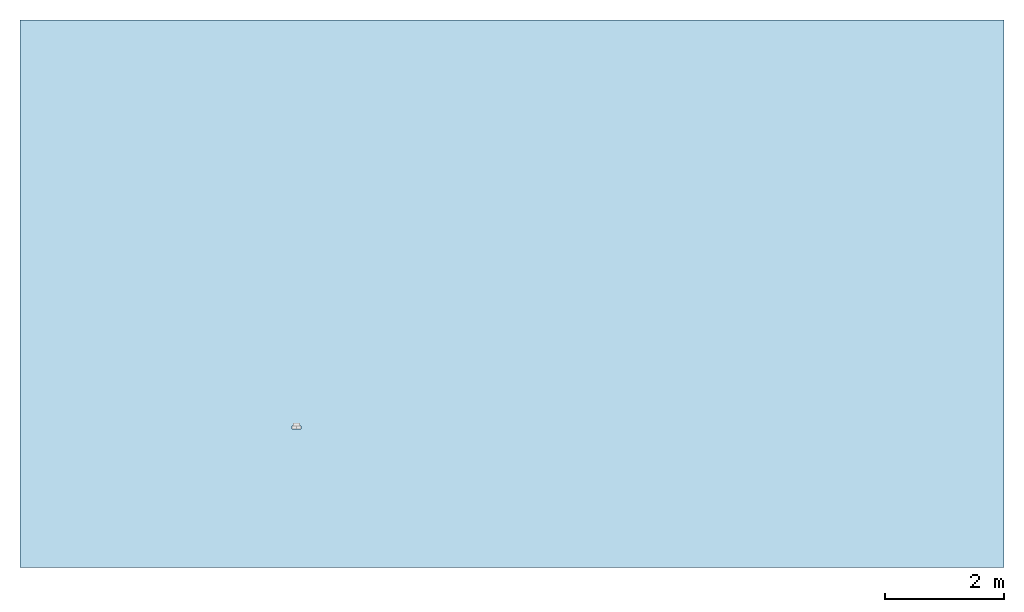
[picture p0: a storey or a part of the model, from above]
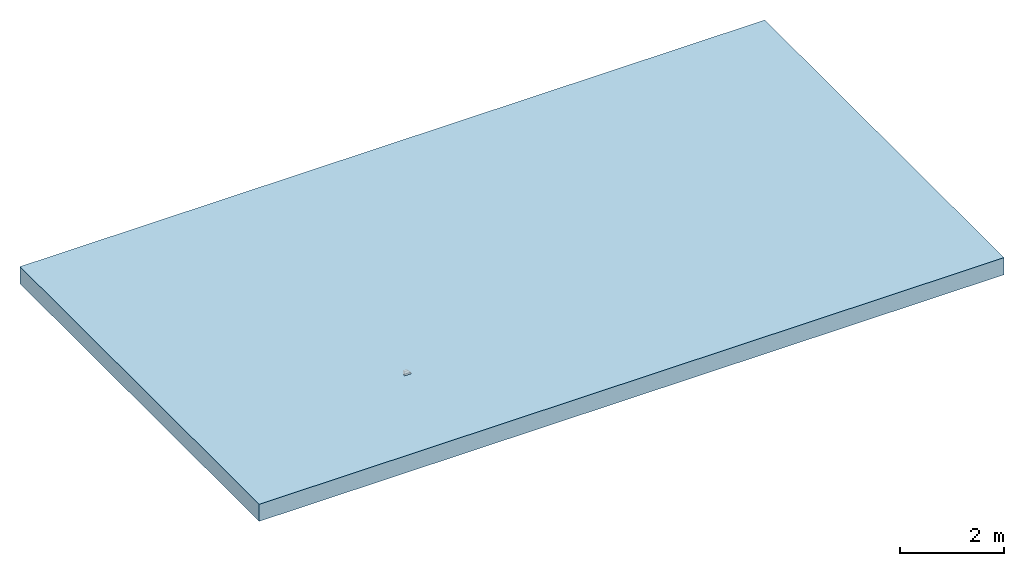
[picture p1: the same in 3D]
Properties of the parts of a building model (IFC2X3)

# File
Description: ViewDefinition [CoordinationView]
File name: 4247 - LH inlet-outlet end cap.ifc
Time: 2013-09-02T12:24:39
Written by: Autodesk Revit 2013
Made in: 20120221_2030(x64)

# IfcProject, Project Number
LongName: Project Name; Phase: Project Status

# IfcSite, Default
RefLatitude: 42, 21, 30, 344238; RefLongitude: -71, -3, -35, -194702; RefElevation: 0 mm

# IfcBuilding
Pset_BuildingCommon - NumberOfStoreys: 1
Other - Project Issue Date: Issue Date; Project Number: Project Number; Project Address: ## Street City, State Zip; Project Name: Project Name; Client Name: Owner; Project Status: Project Status

# IfcBuildingStorey, Level 1
LongName: Level 1; Elevation: 0 mm
Constraints - Elevation Base: 0; Elevation: 0 mm
Graphics - Line Weight: 1; Symbol: M_Level Head - Circle: M_Level Head - Circle; Symbol at End 2 Default: yes; Color: 0; Line Pattern: Center; Symbol at End 1 Default: no
Dimensions - Computation Height: 0 mm
Identity Data - Structural: no; Name: Level 1; Building Story: yes

# IfcBuildingElementProxy: 4247 - LH inlet/outlet end cap, Civil-Drainage-Channel-ACO-KerbDrain-SP380:4247 - LH inlet/outlet end cap:4247 - LH inlet/outlet end cap:308659
In: Level 1
Material: Orange, ACO Polymer Concrete.
Other - Revision: 1; CreatedBy: www.aco.co.uk
Constraints - Level: Level: Level 1; Moves With Nearby Elements: no
Phasing - Phase Created: New Construction
Dimensions - Volume: 2398380 mm3; Void Depth: -280 mm; Void Length: 50 mm; Void Width: 150 mm; AccessDepth: 2000 mm; Access hole: 2 mm; Endcap void: 329.99 mm
Pset_BuildingElementProxyCommon - Reference: 4247 - LH inlet/outlet end cap
Green Building Properties - End Cap Recycled Material Content: 20% minimum; End Cap Recyclable: Fully recyclable; Access Cover/Frame Recyclable: N/A; Access Cover/Frame Recycled Material Content: N/A; Channel Recyclable: N/A; Channel Recycled Material Content: N/A
Identity Data - Installation guidelines: http://www.aco.co.uk/download.php?id=120; Cost: 0; Model Description: Combined kerb and drainage system; e-mail Technical: technical@aco.co.uk; Maintenance guidelines: http://www.aco.co.uk/download.php?id=120; Telephone: +44 (0)1462 816666; Price: POA - contact ACO; Fax: +44 (0)1462 815895; Product Page URL: http://www.aco.co.uk/product_detail.php?id=3; Assembly Code: D2040; Manufacturer: ACO Technologies plc - ACO Water Management Division; Assembly Description: Rain Water Drainage; Product Code: 4247; Type Comments: ACO KerbDrain SP380 splayed LH inlet / outlet end cap; OmniClass Title: Rainwater Removal; e-mail Sales: customersupport@aco.co.uk; Address: ACO Business Park, Hitchin Road, Shefford, Bedfordshire, United Kingdom SG17 5TE; Model: ACO KerbDrain SP380; OmniClass Number: 23.70.50.24; Product brochure: http://www.aco.co.uk/download.php?id=120; URL: www.aco.co.uk
Data - Drainage Slot Width: N/A; Concrete Surround Volume - Load Class A 15 - D 400 - Grass or Asphalt Pavement: N/A; Drainage Slot Intake area: N/A; Product Dimensions: 50mm x 150mm x 380mm (LxWxH); Channel C.S.A: N/A; Product Standard: N/A; Concrete Surround Volume - Load Class A 15 - D 400 - Concrete Pavement: N/A; Product Weight: 5.1 Kg; Hydraulic Performance: N/A; Load Class: N/A; Installation - Concrete Grade: N/A; Invert Depth: N/A; Connection Pipe O.D: Ø110mm; ACO Hydraulic Design Software: N/A
General - TagNumber: 0.000000; SerialNumber: 0.000000
Materials and Finishes - Connection Pipe Material Colour: Brown; Channel Colour: N/A; Access Cover/Frame Material: N/A; Channel Material: N/A; Access Cover/Frame Finish: N/A; End Cap Colour: Grey; Connection Pipe Material: PVCu; Access Cover/Frame Colour: N/A; End Cap Material: Vienite® Synthetic Resin Concrete
Construction - SP380 - 1000: no; LH drop kerb: no; LH transition unit: no; LH inlet/outlet end cap: yes; Closing end cap: no; SP380-500: no; RH transition unit: no; RH inlet/outlet end cap: no; Centre Stone: no; Access Unit: no; RH drop kerb: no

# IfcOpeningElement: Recess (2)
In: Level 1
Constraints - Level: Level: Level 1; Room Bounding: yes; Height Offset From Level: 0 mm; Related to Mass: no
Structural - Enable Analytical Model: no; Structural: no
Dimensions - Thickness: 400 mm; Perimeter: 51360 mm; Area: 151470000 mm2; Volume: 60585431385 mm3
Phasing - Phase Created: New Construction
Construction - Function: 0; Default Thickness: 400 mm
Analytical Properties - Roughness: 1; Absorptance: 0.1
Graphics - Coarse Scale Fill Color: 0
Materials and Finishes - Structural Material: Plant

# IfcSlab: Floor:Generic Floor - 400mm, Floor:Generic Floor - 400mm:193825
In: Level 1
PredefinedType: FLOOR; Material: Plant 400 mm
Constraints - Level: Level: Level 1; Room Bounding: yes; Height Offset From Level: 0 mm; Related to Mass: no
Structural - Enable Analytical Model: no; Structural: no
Dimensions - Thickness: 400 mm; Perimeter: 51360 mm; Area: 151470000 mm2; Volume: 60585431385 mm3
Phasing - Phase Created: New Construction
Pset_SlabCommon - Reference: Generic Floor - 400mm; IsExternal: no; LoadBearing: yes
Construction - Function: 0; Default Thickness: 400 mm
Analytical Properties - Roughness: 1; Absorptance: 0.1
Graphics - Coarse Scale Fill Color: 0
Materials and Finishes - Structural Material: Plant
